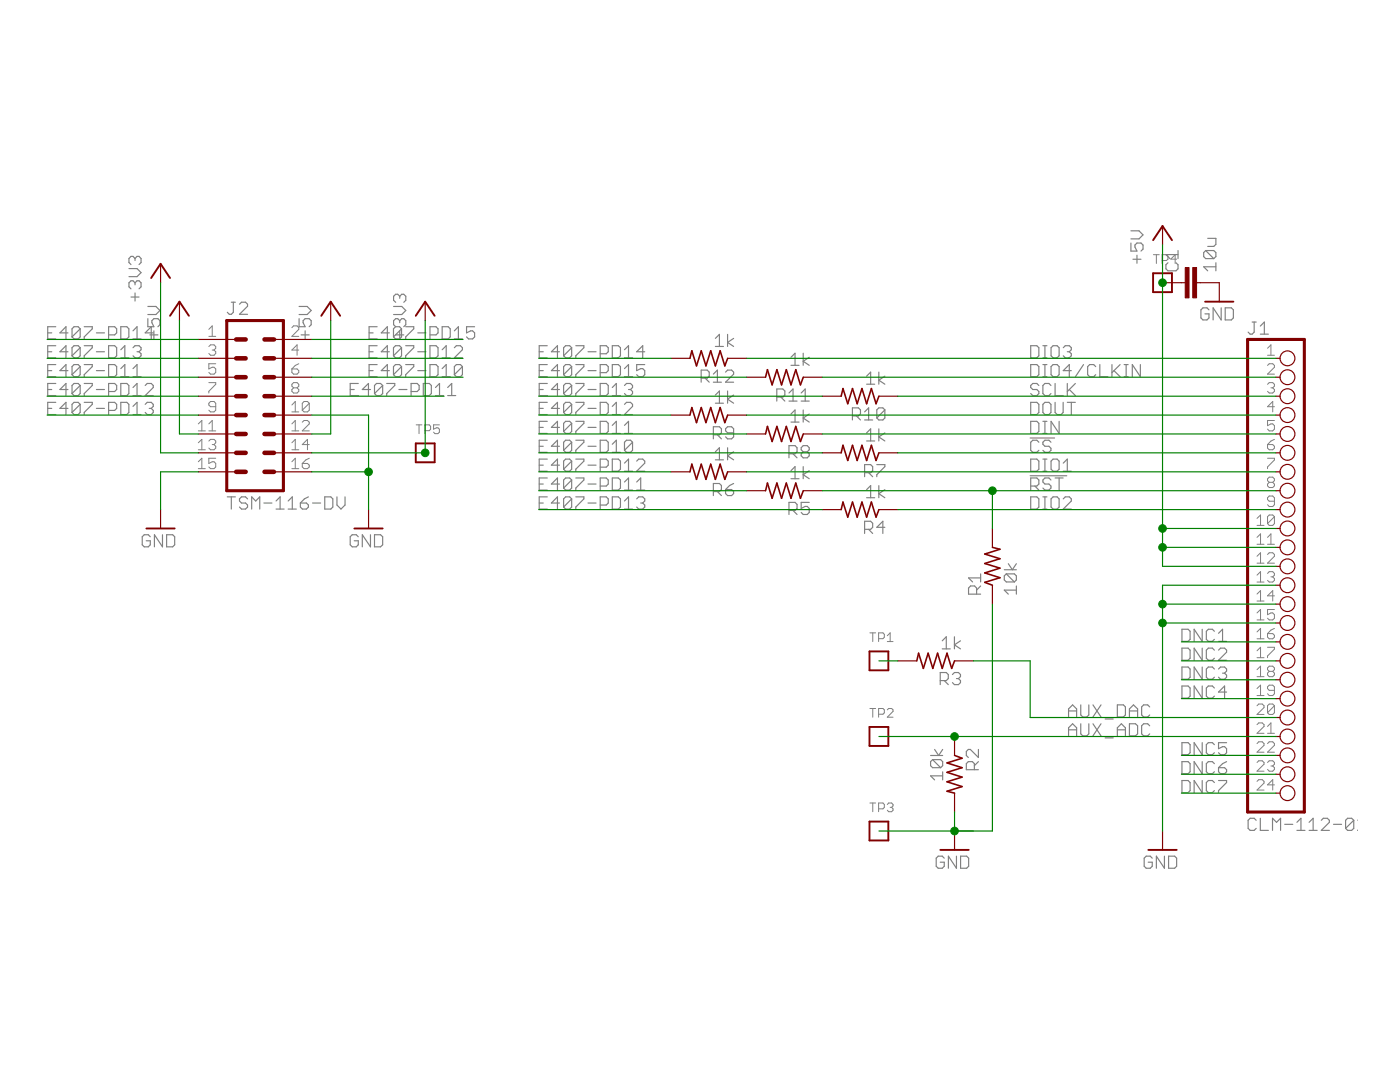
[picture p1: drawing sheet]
<svg xmlns="http://www.w3.org/2000/svg" width="279mm" height="216mm" viewBox="0 0 279 216" stroke-linecap="round" stroke-linejoin="round" font-family="sans-serif">
<g fill="none" stroke="#808080" stroke-width=".23">
<path d="M25.7 53.6h1.6l.9 .8-.9 .8h-1.6M26.1 59.3h1.6M26.9 51.6v.4M26.9 56.4v.4M26.9 58.5v1.6M26.9 56.4l-.4-.4h-.4l-.4 .4v.8l.4 .4M26.9 51.6l-.4-.4h-.4l-.4 .4v.8l.4 .4M26.9 56.4l.4-.4h.4l.5 .4v.8l-.5 .4M26.9 51.6l.4-.4h.4l.5 .4v.8l-.5 .4M79.8 59.1v.4M79.8 59.1l-.4-.4h-.4l-.5 .4v.8l.5 .4M79.8 59.1l.4-.4h.4l.4 .4v.8l-.4 .4"/>
<path d="M225.7 48.5v1.6h1.2l-.4-.8v-.4l.4-.4h.8l.4 .4v.8l-.4 .4M225.7 46.1h1.6l.8 .8-.8 .8h-1.6M226.1 51.7h1.6M226.9 50.9v1.6M233.1 52.4l-.4 .4v.8l.4 .4h1.6l.4-.4v-.8l-.4-.4M235.1 50v1.6M235.1 50.8h-2.4l.8 .8M240.6 50h1.6l.5 .4v.8l-.5 .4M240.6 50l-.4 .4v.8l.4 .4h1.6M240.6 50l1.6 1.6M241 47.6h1.7v1.2l-.5 .4h-1.2M242.7 53.2h-2.5l.8 .8"/>
<path d="M242.7 52.4v1.6M9.5 74h.8M9.5 70.2h.8M9.5 77.7h.8M9.5 66.4h.8M11.1 65.2h-1.6v2.4h1.6M11.1 72.7h-1.6v2.5h1.6M11.1 69h-1.6v2.4h1.6M11.1 76.5h-1.6v2.4h1.6M13.6 70.2h-1.6l1.2-1.2v2.4M13.6 74h-1.6l1.2-1.3v2.5M13.6 77.7h-1.6l1.2-1.2v2.4"/>
<path d="M13.6 66.4h-1.6l1.2-1.2v2.4M16 65.6l-.4-.4h-.8l-.4 .4v1.6M16 73.2v1.6l-.4 .4h-.8l-.4-.4M16 73.2l-.4-.5h-.8l-.4 .5v1.6M16 69.4v1.6l-.4 .4h-.8l-.4-.4M16 69.4l-.4-.4h-.8l-.4 .4v1.6M16 76.9l-.4-.4h-.8l-.4 .4v1.6M16 76.9v1.6l-.4 .4h-.8l-.4-.4M16 65.6v1.6l-.4 .4h-.8l-.4-.4M16 65.6l-1.6 1.6M16 69.4l-1.6 1.6M16 73.2l-1.6 1.6"/>
<path d="M16 76.9l-1.6 1.6M16.8 65.2h1.6v.4l-1.6 1.6v.4M16.8 72.7h1.6v.5l-1.6 1.6v.4M16.8 69h1.6v.4l-1.6 1.6v.4M16.8 76.5h1.6v.4l-1.6 1.6v.4M19.2 74h1.6M19.2 70.2h1.6M19.2 77.7h1.6M19.2 66.4h1.6M21.7 66.8h1.2l.4-.4v-.8l-.4-.4h-1.2v2.4M21.7 69h1.2l.4 .4v1.6l-.4 .4h-1.2zM21.7 72.7h1.2l.4 .5v1.6l-.4 .4h-1.2z"/>
<path d="M21.7 78.1h1.2l.4-.4v-.8l-.4-.4h-1.2v2.4M24.1 65.2h1.2l.4 .4v1.6l-.4 .4h-1.2zM24.1 75.2h1.6M24.1 71.4h1.6M24.1 76.5h1.2l.4 .4v1.6l-.4 .4h-1.2zM24.1 69.8l.8-.8v2.4M24.1 73.6l.8-.9v2.5M26.5 69.4l.4-.4h.8l.5 .4v.4l-.5 .4M26.5 75.2h1.7M26.5 78.9h1.7M26.5 67.6h1.7M26.5 66l.8-.8v2.4"/>
<path d="M26.5 73.6l.8-.9v2.5M26.5 77.3l.8-.8v2.4M27.3 70.2h.4M27.7 70.2l.5 .4v.4l-.5 .4h-.8l-.4-.4M29 76.9l.4-.4h.8l.4 .4v.4l-1.6 1.6h1.6M29.5 63.6v1.6h1.2l-.4-.8v-.4l.4-.4h.8l.4 .4v.8l-.4 .4M29.5 61.2h1.6l.8 .8-.8 .8h-1.6M29.9 66.8h1.6M30.6 66.4h-1.6l1.2-1.2v2.4M30.7 66v1.6M46.2 60.3h.8M46.6 60.3v2l-.4 .4h-.4l-.4-.4"/>
<path d="M47.8 60.7l.4-.4h.8l.4 .4v.4l-1.6 1.6h1.6M59.7 63.6v1.6h1.2l-.4-.8v-.4l.4-.4h.8l.4 .4v.8l-.4 .4M59.7 61.2h1.6l.8 .8-.8 .8h-1.6M60.1 66.8h1.6M60.9 66v1.6M69.9 77.7h.8M71.5 76.5h-1.6v2.4h1.6M73.7 74h.8M73.7 70.2h.8M73.7 66.4h.8M73.9 77.7h-1.6l1.2-1.2v2.4M75.3 65.2h-1.6v2.4h1.6"/>
<path d="M75.3 72.7h-1.6v2.5h1.6M75.3 69h-1.6v2.4h1.6M76.4 76.9l-.5-.4h-.8l-.4 .4v1.6M76.4 76.9v1.6l-.5 .4h-.8l-.4-.4M76.4 76.9l-1.7 1.6M77.2 76.5h1.6v.4l-1.6 1.6v.4M77.7 74h-1.6l1.2-1.3v2.5M77.7 70.2h-1.6l1.2-1.2v2.4M77.7 66.4h-1.6l1.2-1.2v2.4M78.5 61.2h1.7l.8 .8-.8 .8h-1.7M79 66.8h1.6M79.6 77.7h1.6"/>
<path d="M79.8 64l-.4-.4h-.4l-.5 .4v.8l.5 .4M79.8 64l.4-.4h.4l.4 .4v.8l-.4 .4M79.8 64v.4M79.8 66v1.6M80.1 65.6l-.4-.4h-.8l-.4 .4v1.6M80.1 69.4l-.4-.4h-.8l-.4 .4v1.6M80.1 73.2l-.4-.5h-.8l-.4 .5v1.6M80.1 65.6l-1.6 1.6M80.1 73.2v1.6l-.4 .4h-.8l-.4-.4M80.1 69.4v1.6l-.4 .4h-.8l-.4-.4M80.1 65.6v1.6l-.4 .4h-.8l-.4-.4M80.1 69.4l-1.6 1.6"/>
<path d="M80.1 73.2l-1.6 1.6M81 65.2h1.6v.4l-1.6 1.6v.4M81 69h1.6v.4l-1.6 1.6v.4M81 72.7h1.6v.5l-1.6 1.6v.4M82 78.1h1.2l.5-.4v-.8l-.5-.4h-1.2v2.4M83.4 74h1.6M83.4 70.2h1.6M83.4 66.4h1.6M84.5 76.5h1.2l.4 .4v1.6l-.4 .4h-1.2zM85.8 66.8h1.2l.4-.4v-.8l-.4-.4h-1.2v2.4M85.8 72.7h1.2l.4 .5v1.6l-.4 .4h-1.2zM85.8 69h1.2l.4 .4v1.6l-.4 .4h-1.2z"/>
<path d="M86.9 78.9h1.6M86.9 77.3l.8-.8v2.4M88.2 65.2h1.3l.4 .4v1.6l-.4 .4h-1.3zM88.2 75.2h1.7M88.2 71.4h1.7M88.2 69.8l.8-.8v2.4M88.2 73.6l.8-.9v2.5M89.3 78.9h1.7M89.3 77.3l.8-.8v2.4M90.7 69.4l.4-.4h.8l.4 .4v.4l-1.6 1.6h1.6M90.7 67.6h1.6M90.7 66l.8-.8v2.4"/>
<path d="M92.3 73.2v1.6l-.4 .4h-.8l-.4-.4M92.3 73.2l-.4-.5h-.8l-.4 .5v1.6M92.3 73.2l-1.6 1.6M94.7 65.2h-1.6v1.2l.8-.4h.4l.4 .4v.8l-.4 .4h-.8l-.4-.4M107.6 74h.8M107.6 70.2h.8M107.6 77.7h.8M109.2 72.7h-1.6v2.5h1.6M109.2 69h-1.6v2.4h1.6M109.2 76.5h-1.6v2.4h1.6M111.7 70.2h-1.7l1.3-1.2v2.4M111.7 74h-1.7l1.3-1.3v2.5"/>
<path d="M111.7 77.7h-1.7l1.3-1.2v2.4M114.1 73.2v1.6l-.4 .4h-.8l-.4-.4M114.1 73.2l-.4-.5h-.8l-.4 .5v1.6M114.1 69.4v1.6l-.4 .4h-.8l-.4-.4M114.1 69.4l-.4-.4h-.8l-.4 .4v1.6M114.1 76.9l-.4-.4h-.8l-.4 .4v1.6M114.1 76.9v1.6l-.4 .4h-.8l-.4-.4M114.1 69.4l-1.6 1.6M114.1 73.2l-1.6 1.6M114.1 76.9l-1.6 1.6M114.9 72.7h1.6v.5l-1.6 1.6v.4M114.9 69h1.6v.4l-1.6 1.6v.4"/>
<path d="M114.9 76.5h1.6v.4l-1.6 1.6v.4M117.3 74h1.7M117.3 70.2h1.7M117.3 77.7h1.7M119.8 74.4h1.2l.4-.4v-.8l-.4-.5h-1.2v2.5M119.8 70.6h1.2l.4-.4v-.8l-.4-.4h-1.2v2.4M119.8 76.5h1.2l.4 .4v1.6l-.4 .4h-1.2zM122.2 72.7h1.2l.4 .5v1.6l-.4 .4h-1.2zM122.2 69h1.2l.4 .4v1.6l-.4 .4h-1.2zM122.2 78.9h1.6M122.2 77.3l.8-.8v2.4M124.6 75.2h1.6"/>
<path d="M124.6 71.4h1.6M124.6 76.9l.4-.4h.8l.4 .4v.4l-.4 .4M124.6 69.8l.8-.8v2.4M124.6 73.6l.8-.9v2.5M125.4 77.7h.4M125.8 77.7l.4 .4v.4l-.4 .4h-.8l-.4-.4M128.7 72.7h-1.6v1.3l.8-.4h.4l.4 .4v.8l-.4 .4h-.8l-.4-.4M128.7 70.2h-1.6l1.2-1.2v2.4M139.9 75.5h1.2l.4-.4v-.8l-.4-.4h-1.2v2.4M140.7 75.5l.8 .8M142.4 74.7l.8-.8v2.4M142.4 76.3h1.6"/>
<path d="M142.8 67.5l.8-.8v2.4M142.8 78.8l.8-.8v2.5M142.8 69.1h1.6M144.8 74.3l.4-.4h.8l.4 .4v.4l-1.6 1.6h1.6M145.2 66.7v2.4M145.2 78v2.5M146.4 78.8l-1.2 .9 1.2 .8M146.4 67.5l-1.2 .8 1.2 .8M155 79.2h1.2l.4-.4v-.8l-.4-.4h-1.2v2.4M155.8 79.2l.8 .8M157.5 78.4l.8-.8v2.4M157.9 71.3l.8-.8v2.4"/>
<path d="M157.9 72.9h1.6M159.9 78.4l.8-.8v2.4M160.3 70.5v2.4M161.5 71.3l-1.2 .8 1.2 .8M173 75.1l.8-.8v2.4M173 76.7h1.6M175.4 74.3v2.4M176.6 75.1l-1.2 .8 1.2 .8M205.7 69h1.2l.4 .4v1.6l-.4 .4h-1.2zM205.7 72.7h1.2l.4 .5v1.6l-.4 .4h-1.2zM207.3 76.9l-.4-.4h-.8l-.4 .4v.4l.4 .4h.8l.4 .4v.4l-.4 .4h-.8l-.4-.4M208.1 75.2h.8"/>
<path d="M208.1 72.7h.8M208.1 71.4h.8M208.1 69h.8M208.5 69v2.4M208.5 72.7v2.5M209.7 76.9l-.4-.4h-.8l-.4 .4v1.6l.4 .4h.8l.4-.4M209.8 73.2l.4-.5h.8l.4 .5v1.6l-.4 .4h-.8l-.4-.4zM210.2 69h.8l.4 .4v1.6l-.4 .4h-.8l-.4-.4v-1.6zM210.6 76.5v2.4h1.6M212.2 69.4l.4-.4h.8l.4 .4v.4l-.4 .4M213 70.2h.4M213 76.5v2.4"/>
<path d="M213.4 70.2l.4 .4v.4l-.4 .4h-.8l-.4-.4M213.4 77.7l1.2 1.2M213.8 74h-1.6l1.2-1.3v2.5M214.6 76.5l-1.6 1.6M216.2 72.7l-1.6 2.5M218.7 73.2l-.4-.5h-.8l-.4 .5v1.6l.4 .4h.8l.4-.4M219.5 72.7v2.5h1.6M221.9 72.7v2.5M222.3 74l1.2 1.2M223.5 72.7l-1.6 1.7M224.3 75.2h.8M224.3 72.7h.8"/>
<path d="M224.7 72.7v2.5M227.6 72.7v2.5l-1.6-2.5v2.5M241.3 61.8l-.4-.4h-.8l-.4 .4v1.6l.4 .4h.8l.4-.4v-.8h-.8M243.7 61.4v2.4l-1.6-2.4v2.4M244.5 61.4h1.2l.4 .4v1.6l-.4 .4h-1.2zM249.9 64.3h.8M250.3 64.3v2l-.4 .4h-.4l-.4-.4M251.5 66.7h1.6M251.5 65.1l.8-.8v2.4M9.5 81.5h.8M11.1 80.3h-1.6v2.4h1.6M13.6 81.5h-1.6l1.2-1.2v2.4"/>
<path d="M16 80.7v1.6l-.4 .4h-.8l-.4-.4M16 80.7l-.4-.4h-.8l-.4 .4v1.6M16 80.7l-1.6 1.6M16.8 80.3h1.6v.4l-1.6 1.6v.4M19.2 81.5h1.6M21.7 81.9h1.2l.4-.4v-.8l-.4-.4h-1.2v2.4M24.1 80.3h1.2l.4 .4v1.6l-.4 .4h-1.2zM26.5 82.7h1.7M26.5 81.1l.8-.8v2.4M29 80.7l.4-.4h.8l.4 .4v.4l-.4 .4M29.8 81.5h.4M30.2 81.5l.4 .4v.4l-.4 .4h-.8l-.4-.4"/>
<path d="M45.4 99.1h1.6M46.2 99.1v2.5M49.4 99.5l-.4-.4h-.8l-.4 .4v.5l.4 .4h.8l.4 .4v.4l-.4 .4h-.8l-.4-.4M55.1 100l.8-.9v2.5M57.5 100l.8-.9v2.5M61.6 99.1l-.9 .4-.8 .9M64.8 99.1h1.2l.4 .4v1.7l-.4 .4h-1.2zM67.2 99.1v1.7l.9 .8 .8-.8v-1.7M107.6 89h.8M107.6 96.6h.8M107.6 81.5h.8M107.6 85.3h.8"/>
<path d="M107.6 92.8h.8M109.2 99.1h-1.6v2.5h1.6M109.2 80.3h-1.6v2.4h1.6M109.2 87.8h-1.6v2.5h1.6M109.2 91.6h-1.6v2.4h1.6M109.2 95.4h-1.6v2.4h1.6M109.2 84.1h-1.6v2.4h1.6M111.7 89h-1.7l1.3-1.2v2.5M111.7 96.6h-1.7l1.3-1.2v2.4M111.7 81.5h-1.7l1.3-1.2v2.4M111.7 85.3h-1.7l1.3-1.2v2.4M111.7 92.8h-1.7l1.3-1.2v2.4"/>
<path d="M114.1 99.5l-.4-.4h-.8l-.4 .4v1.7M114.1 99.5v1.7l-.4 .4h-.8l-.4-.4M114.1 80.7v1.6l-.4 .4h-.8l-.4-.4M114.1 80.7l-.4-.4h-.8l-.4 .4v1.6M114.1 88.2l-.4-.4h-.8l-.4 .4v1.7M114.1 88.2v1.7l-.4 .4h-.8l-.4-.4M114.1 92v1.6l-.4 .4h-.8l-.4-.4M114.1 92l-.4-.4h-.8l-.4 .4v1.6M114.1 95.8l-.4-.4h-.8l-.4 .4v1.6M114.1 95.8v1.6l-.4 .4h-.8l-.4-.4M114.1 84.5l-.4-.4h-.8l-.4 .4v1.6M114.1 84.5v1.6l-.4 .4h-.8l-.4-.4"/>
<path d="M114.1 80.7l-1.6 1.6M114.1 84.5l-1.6 1.6M114.1 88.2l-1.6 1.7M114.1 92l-1.6 1.6M114.1 95.8l-1.6 1.6M114.1 99.5l-1.6 1.7M114.9 99.1h1.6v.4l-1.6 1.7v.4M114.9 80.3h1.6v.4l-1.6 1.6v.4M114.9 87.8h1.6v.4l-1.6 1.7v.4M114.9 91.6h1.6v.4l-1.6 1.6v.4M114.9 95.4h1.6v.4l-1.6 1.6v.4M114.9 84.1h1.6v.4l-1.6 1.6v.4"/>
<path d="M117.3 89h1.7M117.3 96.6h1.7M117.3 81.5h1.7M117.3 85.3h1.7M117.3 92.8h1.7M119.8 80.3h1.2l.4 .4v1.6l-.4 .4h-1.2zM119.8 87.8h1.2l.4 .4v1.7l-.4 .4h-1.2zM119.8 93.2h1.2l.4-.4v-.8l-.4-.4h-1.2v2.4M119.8 97h1.2l.4-.4v-.8l-.4-.4h-1.2v2.4M119.8 84.1h1.2l.4 .4v1.6l-.4 .4h-1.2zM122.2 99.1h1.2l.4 .4v1.7l-.4 .4h-1.2zM122.2 82.7h1.6"/>
<path d="M122.2 90.3h1.6M122.2 91.6h1.2l.4 .4v1.6l-.4 .4h-1.2zM122.2 95.4h1.2l.4 .4v1.6l-.4 .4h-1.2zM122.2 81.1l.8-.8v2.4M122.2 84.9l.8-.8v2.4M122.2 88.6l.8-.8v2.5M122.2 86.5h1.6M124.6 92.4l.8-.8v2.4M124.6 80.7l.4-.4h.8l.4 .4v.4l-1.6 1.6h1.6M124.6 94h1.6M124.6 97.8h1.6M124.6 86.5h1.6"/>
<path d="M124.6 84.9l.8-.8v2.4M124.6 96.2l.8-.8v2.4M124.6 100l.8-.9v2.5M126.2 88.2l-.4-.4h-.8l-.4 .4v1.7M126.2 88.2v1.7l-.4 .4h-.8l-.4-.4M126.2 88.2l-1.6 1.7M127.1 99.5l.4-.4h.8l.4 .4v.5l-.4 .4M127.1 92l.4-.4h.8l.4 .4v.4l-1.6 1.6h1.6M127.1 97.8h1.6M127.1 96.2l.8-.8v2.4M142.4 86.8h1.2l.4-.4v-.8l-.4-.4h-1.2v2.4M142.4 98.1h1.2l.4-.4v-.8l-.4-.4h-1.2v2.4"/>
<path d="M142.8 90.1l.8-.8v2.5M142.8 91.8h1.6M142.8 80.5h1.6M143.2 98.1l.8 .8M143.2 86.8l.8 .8M144.8 97.7h1.2l.4 .4v.4l-.4 .4h-.8l-.4-.4zM145.2 89.3v2.5M146.4 90.1l-1.2 .9 1.2 .8M146.4 86.4h-1.2l-.4-.4v-.4l.4-.4h.8l.4 .4v1.6l-.4 .4h-.8l-.4-.4M146.4 96.5l-.8 .4-.8 .8M157.5 90.6h1.2l.4-.5v-.8l-.4-.4h-1.2v2.5M157.5 80h1.6"/>
<path d="M157.9 93.9l.8-.8v2.4M157.9 82.6l.8-.8v2.4M157.9 95.5h1.6M157.9 84.2h1.6M158.3 90.6l.8 .8M159.9 80h1.6M160.3 81.8v2.4M160.3 93.1v2.4M160.3 90.1l-.4-.4v-.4l.4-.4h.8l.4 .4v.4l-.4 .4M160.3 90.1l-.4 .5v.4l.4 .4h.8l.4-.4v-.4l-.4-.5M160.3 90.1h.8M161.5 93.9l-1.2 .8 1.2 .8"/>
<path d="M161.5 82.6l-1.2 .8 1.2 .8M170.1 83h1.2l.4-.4v-.8l-.4-.4h-1.2v2.4M170.9 83l.8 .8M172.6 94.3h1.2l.4-.4v-.8l-.4-.4h-1.2v2.4M172.6 82.2l.8-.8v2.4M172.6 83.8h1.6M173 97.7l.8-.8v2.4M173 86.4l.8-.8v2.4M173 99.3h1.6M173 88h1.6M173.4 94.3l.8 .8M175 92.7h1.6v.4l-1.6 1.6v.4"/>
<path d="M175.4 85.6v2.4M175.4 96.9v2.4M176.6 97.7l-1.2 .8 1.2 .8M176.6 86.4l-1.2 .8 1.2 .8M176.6 81.8v1.6l-.4 .4h-.8l-.4-.4M176.6 81.8l-.4-.4h-.8l-.4 .4v1.6M176.6 81.8l-1.6 1.6M205.6 87.4h4.9M205.6 94.9h7.3M205.7 99.1h1.2l.4 .4v1.7l-.4 .4h-1.2zM205.7 80.3h1.2l.4 .4v1.6l-.4 .4h-1.2zM205.7 84.1h1.2l.4 .4v1.6l-.4 .4h-1.2z"/>
<path d="M205.7 91.6h1.2l.4 .4v1.6l-.4 .4h-1.2zM205.7 97h1.2l.4-.4v-.8l-.4-.4h-1.2v2.4M206.5 97l.8 .8M207.3 88.2l-.4-.4h-.8l-.4 .4v1.7l.4 .4h.8l.4-.4M208.1 99.1h.8M208.1 80.7l.4-.4h.8l.4 .4v1.6l-.4 .4h-.8l-.4-.4zM208.1 94h.8M208.1 91.6h.8M208.1 86.5h.8M208.1 84.1h.8M208.5 84.1v2.4M208.5 91.6v2.4"/>
<path d="M208.5 99.1v2.5M209.7 88.2l-.4-.4h-.8l-.4 .4v.4l.4 .4h.8l.4 .5v.4l-.4 .4h-.8l-.4-.4M209.7 95.8l-.4-.4h-.8l-.4 .4v.4l.4 .4h.8l.4 .4v.4l-.4 .4h-.8l-.4-.4M209.8 92l.4-.4h.8l.4 .4v1.6l-.4 .4h-.8l-.4-.4zM210.2 99.1h.8l.4 .4v1.7l-.4 .4h-.8l-.4-.4v-1.7zM210.6 80.3v2l.4 .4h.8l.4-.4v-2M210.6 95.4h1.6M211.4 84.1v2.4l-1.6-2.4v2.4M211.4 95.4v2.4M212.2 99.5l.4-.4h.8l.4 .4v.5l-1.6 1.6h1.6M212.2 92.4l.8-.8v2.4M212.2 94h1.6"/>
<path d="M213 80.3h1.6M213.8 80.3v2.4M30 107.1l-.4-.4h-.8l-.4 .4v1.6l.4 .4h.8l.4-.4v-.8h-.8M32.4 106.7v2.4l-1.6-2.4v2.4M33.3 106.7h1.2l.4 .4v1.6l-.4 .4h-1.2zM50.2 101.6v-2.5l.8 .9 .8-.9v2.5M52.7 100.4h1.6M55.1 101.6h1.6M57.5 101.6h1.6M59.9 100.4h1.3l.4 .4v.4l-.4 .4h-.9l-.4-.4zM62.4 100.4h1.6M71.5 107.1l-.4-.4h-.8l-.4 .4v1.6l.4 .4h.8l.4-.4v-.8h-.8"/>
<path d="M73.9 106.7v2.4l-1.6-2.4v2.4M74.7 106.7h1.2l.5 .4v1.6l-.5 .4h-1.2zM107.6 100.4h.8M111.7 100.4h-1.7l1.3-1.3v2.5M117.3 100.4h1.7M119.8 100.8h1.2l.4-.4v-.9l-.4-.4h-1.2v2.5M124.6 101.6h1.6M127.9 100.4h.4M128.3 100.4l.4 .4v.4l-.4 .4h-.8l-.4-.4M157.5 101.9h1.2l.4-.4v-.9l-.4-.4h-1.2v2.5M158.3 101.9l.8 .8M161.5 100.2h-1.6v1.3l.8-.5h.4l.4 .5v.8l-.4 .4h-.8l-.4-.4"/>
<path d="M172.6 105.6h1.2l.4-.4v-.8l-.4-.4h-1.2v2.4M173.4 105.6l.8 .8M176.6 105.2h-1.6l1.2-1.2v2.4M194.9 118.6v-1.3l-.4-.4h-.8l-.4 .4v1.3h2.4M195.7 116.9l-.8 .9M195.7 115.3h-2.4l.8 .8M195.7 114.5v1.6M200.4 113.7h2.4M200.8 114.5h1.6l.4 .4v.8l-.4 .4M200.8 114.5l-.4 .4v.8l.4 .4h1.6M200.8 114.5l1.6 1.6M201.2 112.5l.8 1.2 .8-1.2"/>
<path d="M202.8 117.8h-2.4l.8 .8M202.8 116.9v1.7M208.1 101.6h.8M187.6 135.8h1.2l.5-.4v-.8l-.5-.4h-1.2v2.4M188 127.9l.8-.8v2.4M188 129.5h1.7M188.4 135.8l.9 .8M190.1 134.6l.4-.4h.8l.4 .4v.4l-.4 .4M190.5 127.1v2.4M190.9 135.4h.4M191.3 135.4l.4 .4v.4l-.4 .4h-.8l-.4-.4M191.7 127.9l-1.2 .8 1.2 .8"/>
<path d="M235.9 125.6h1.2l.4 .4v1.6l-.4 .4h-1.2zM235.9 129.3h1.2l.4 .4v1.6l-.4 .4h-1.2zM235.9 133.1h1.2l.4 .4v1.6l-.4 .4h-1.2zM235.9 136.9h1.2l.4 .4v1.6l-.4 .4h-1.2zM239.9 125.6v2.4l-1.6-2.4v2.4M239.9 129.3v2.4l-1.6-2.4v2.4M239.9 133.1v2.4l-1.6-2.4v2.4M239.9 136.9v2.4l-1.6-2.4v2.4M242.4 126l-.4-.4h-.8l-.5 .4v1.6l.5 .4h.8l.4-.4M242.4 129.7l-.4-.4h-.8l-.5 .4v1.6l.5 .4h.8l.4-.4M242.4 133.5l-.4-.4h-.8l-.5 .4v1.6l.5 .4h.8l.4-.4M242.4 137.3l-.4-.4h-.8l-.5 .4v1.6l.5 .4h.8l.4-.4"/>
<path d="M243.2 128h1.6M243.2 126.4l.8-.8v2.4M243.2 129.7l.4-.4h.8l.4 .4v.4l-1.6 1.6h1.6M243.2 133.5l.4-.4h.8l.4 .4v.4l-.4 .4M244 134.3h.4M244.4 134.3l.4 .4v.4l-.4 .4h-.8l-.4-.4M244.8 138.1h-1.6l1.2-1.2v2.4M185.7 150.7h2.4M186.1 151.6h1.6l.4 .4v.8l-.4 .4M186.1 151.6l-.4 .4v.8l.4 .4h1.6M186.1 151.6l1.6 1.6M186.5 149.5l.8 1.2 .8-1.2"/>
<path d="M188.1 154.8h-2.4l.8 .8M188.1 154v1.6M194.5 153.6v-1.2l-.4-.4h-.8l-.5 .4v1.2h2.5M195.3 149.5v1.7l-1.6-1.7h-.4l-.5 .4v.8l.5 .5M195.3 152l-.8 .8M213.3 143.1v-1.6l.8-.8 .8 .8v1.6M213.3 146.8v-1.6l.8-.8 .8 .8v1.6M213.3 141.9h1.6M213.3 145.6h1.6M215.7 140.7v2l.4 .4h.8l.4-.4v-2M215.7 144.4v2l.4 .4h.8l.4-.4v-2M218.1 140.7l1.6 2.4"/>
<path d="M218.1 144.4l1.6 2.4M219.7 140.7l-1.6 2.4M219.7 144.4l-1.6 2.4M220.6 143.5h1.6M220.6 147.2h1.6M223 140.7h1.2l.4 .4v1.6l-.4 .4h-1.2zM223 146.8v-1.6l.8-.8 .8 .8v1.6M223 145.6h1.6M225.4 141.9h1.6M225.4 143.1v-1.6l.8-.8 .8 .8v1.6M225.4 144.4h1.2l.4 .4v1.6l-.4 .4h-1.2zM229.4 141.1l-.4-.4h-.8l-.4 .4v1.6l.4 .4h.8l.4-.4"/>
<path d="M229.4 144.8l-.4-.4h-.8l-.4 .4v1.6l.4 .4h.8l.4-.4M235.9 152h1.2l.4 .4v1.6l-.4 .4h-1.2zM235.9 148.2h1.2l.4 .4v1.6l-.4 .4h-1.2zM235.9 155.7h1.2l.4 .4v1.7l-.4 .4h-1.2zM239.9 148.2v2.4l-1.6-2.4v2.4M239.9 152v2.4l-1.6-2.4v2.4M239.9 155.7v2.5l-1.6-2.5v2.5M242.4 152.4l-.4-.4h-.8l-.5 .4v1.6l.5 .4h.8l.4-.4M242.4 148.6l-.4-.4h-.8l-.5 .4v1.6l.5 .4h.8l.4-.4M242.4 156.1l-.4-.4h-.8l-.5 .4v1.7l.5 .4h.8l.4-.4M243.2 153.2h1.2l.4 .4v.4l-.4 .4h-.8l-.4-.4zM243.2 155.7h1.6v.4l-1.6 1.7v.4"/>
<path d="M244.8 148.2h-1.6v1.2l.8-.4h.4l.4 .4v.8l-.4 .4h-.8l-.4-.4M244.8 152l-.8 .4-.8 .8M188.4 171.2l-.4-.4h-.8l-.4 .4v1.6l.4 .4h.8l.4-.4v-.8h-.8M190.9 170.8v2.4l-1.6-2.4v2.4M191.7 170.8h1.2l.4 .4v1.6l-.4 .4h-1.2zM230 171.2l-.4-.4h-.9l-.4 .4v1.6l.4 .4h.9l.4-.4v-.8h-.8M232.4 170.8v2.4l-1.6-2.4v2.4M233.2 170.8h1.2l.4 .4v1.6l-.4 .4h-1.2zM250.7 163.7l-.4-.4h-.8l-.4 .4v1.6l.4 .4h.8l.4-.4M251.5 163.3v2.4h1.6M254 165.7v-2.4l.8 .8 .8-.8v2.4M256.4 164.5h1.6"/>
<path d="M258.8 165.7h1.6M258.8 164.1l.8-.8v2.4M261.3 165.7h1.6M261.3 164.1l.8-.8v2.4M263.7 163.7l.4-.4h.8l.4 .4v.4l-1.6 1.6h1.6M266.1 164.5h1.6M270.2 163.7l-.5-.4h-.8l-.4 .4v1.6M270.2 163.7v1.6l-.5 .4h-.8l-.4-.4M270.2 163.7l-1.7 1.6"/>
</g>
<g fill="none" stroke="#808080" stroke-width=".2">
<path d="M230.2 50.8h1.2M230.8 50.8v1.8M231.9 52h.9l.3-.3v-.6l-.3-.3h-.9v1.8M234.8 51.7h-1.1l.8-.9v1.8M41.7 76.3h1.4v.4l-1.4 1.4v.3M41.7 65.7l.7-.7v2.1M41.7 67.1h1.4M41.7 69.2l.3-.4h.7l.4 .4v.3l-.4 .3M42.4 69.8h.3M42.7 69.8l.4 .4v.3l-.4 .4h-.7l-.3-.4M43.1 72.6h-1.4v1l.7-.3h.3l.4 .3v.7l-.4 .4h-.7l-.3-.4M58.3 73.6h1l.3 .4v.3l-.3 .4h-.7l-.3-.4z"/>
<path d="M58.3 65.4l.3-.4h.7l.3 .4v.3l-1.3 1.4h1.3M58.6 77.4l-.3-.4v-.3l.3-.4h.7l.3 .4v.3l-.3 .4M58.6 77.4h.7M58.6 77.4l-.3 .3v.4l.3 .3h.7l.3-.3v-.4l-.3-.3M59.6 69.8h-1.3l1-1v2.1M59.6 72.6l-.7 .3-.6 .7M253 69.5l.6-.7v2.1M253 70.9h1.3M253 72.9l.3-.3h.7l.3 .3v.4l-1.3 1.4h1.3M253 76.7l.3-.4h.7l.3 .4v.3l-.3 .4M253.6 77.4h.4M254 77.4l.3 .3v.4l-.3 .3h-.7l-.3-.3"/>
<path d="M39.6 86h1.4M39.6 89.7h1.4M39.6 84.6l.7-.7v2.1M39.6 88.3l.7-.6v2M39.6 92.1l.7-.7v2.1M39.6 93.5h1.4M41.7 86h1.4M41.7 84.6l.7-.7v2.1M41.7 88l.3-.3h.7l.4 .3v.3l-.4 .4M42.4 88.7h.3M42.7 88.7l.4 .3v.4l-.4 .3h-.7l-.3-.3M43.1 81.2h-1.1l-.3-.4v-.3l.3-.4h.7l.4 .4v1.4l-.4 .3h-.7l-.3-.3"/>
<path d="M43.1 91.4h-1.4v1.1l.7-.4h.3l.4 .4v.7l-.4 .3h-.7l-.3-.3M58.3 86h1.3M58.3 89.7h1.3M58.3 82.2h1.3M58.3 80.8l.6-.7v2.1M58.3 84.6l.6-.7v2.1M58.3 88.3l.6-.6v2M58.3 92.1l.6-.7v2.1M58.3 93.5h1.3M60.3 84.2l.4-.3h.7l.3 .3v.4l-1.4 1.4h1.4M60.3 92.5h1.1l.3 .3v.4l-.3 .3h-.7l-.4-.3zM61.7 88.7h-1.4l1.1-1v2"/>
<path d="M61.7 80.5l-.3-.4h-.7l-.4 .4v1.4M61.7 80.5v1.4l-.3 .3h-.7l-.4-.3M61.7 80.5l-1.4 1.4M61.7 91.4l-.7 .4-.7 .7M83.1 84.8h1.1M83.6 84.8v1.7M84.8 85.9h.9l.2-.3v-.5l-.2-.3h-.9v1.7M87.7 84.8h-1.2v.8l.6-.2h.3l.3 .2v.6l-.3 .3h-.6l-.3-.3M253 88.7h1l.3 .3v.4l-.3 .3h-.7l-.3-.3zM253 91.4h1.3v.4l-1.3 1.4v.3M253.3 96.2l-.3-.3v-.3l.3-.4h.7l.3 .4v.3l-.3 .3M253.3 96.2l-.3 .4v.3l.3 .4h.7l.3-.4v-.3l-.3-.4"/>
<path d="M253.3 96.2h.7M254.3 83.9h-1.3v1l.6-.3h.4l.3 .3v.7l-.3 .4h-.7l-.3-.4M254.3 81.2h-1.3l1-1.1v2.1M254.3 87.7l-.7 .3-.6 .7M250.9 103.4l.7-.6v2M250.9 107.2l.7-.7v2.1M250.9 111l.7-.7v2.1M250.9 114.8l.7-.7v2M250.9 118.5l.7-.6v2M250.9 104.8h1.4M250.9 108.6h1.4M250.9 112.4h1.4"/>
<path d="M250.9 116.1h1.4M250.9 119.9h1.4M253 107.2l.6-.7v2.1M253 110.6l.3-.3h.7l.3 .3v.4l-1.3 1.4h1.3M253 114.4l.3-.3h.7l.3 .3v.4l-.3 .3M253 108.6h1.3M253.6 115.1h.4M254 115.1l.3 .4v.3l-.3 .3h-.7l-.3-.3M254.3 100h-1l-.3-.3v-.4l.3-.3h.7l.3 .3v1.4l-.3 .4h-.7l-.3-.4M254.3 103.1v1.4l-.3 .3h-.7l-.3-.3M254.3 118.9h-1.3l1-1v2M254.3 103.1l-.3-.3h-.7l-.3 .3v1.4"/>
<path d="M254.3 103.1l-1.3 1.4M173.6 126.3h1.2M174.2 126.3v1.7M175.3 127.4h.9l.3-.3v-.5l-.3-.3h-.9v1.7M177.1 126.9l.6-.6v1.7M177.1 128h1.1M250.9 122.3l.7-.7v2.1M250.9 126.1l.7-.7v2.1M250.9 129.9l.7-.7v2M250.9 133.6l.7-.7v2.1M250.9 137.4l.7-.7v2.1M250.9 123.7h1.4"/>
<path d="M250.9 127.5h1.4M250.9 131.2h1.4M250.9 135h1.4M250.9 138.8h1.4M253 126.4h1l.3 .4v.3l-.3 .4h-.7l-.3-.4zM253 129.2h1.3v.3l-1.3 1.4v.3M253.3 134l-.3-.4v-.3l.3-.4h.7l.3 .4v.3l-.3 .4M253.3 134l-.3 .3v.4l.3 .3h.7l.3-.3v-.4l-.3-.3M253.3 134h.7M254.3 121.6h-1.3v1.1l.6-.4h.4l.3 .4v.7l-.3 .3h-.7l-.3-.3M254.3 137.8h-1l-.3-.4v-.3l.3-.4h.7l.3 .4v1.3l-.3 .4h-.7l-.3-.4M254.3 125.4l-.7 .3-.6 .7"/>
<path d="M173.6 141.4h1.2M174.2 141.4v1.7M175.3 142.5h.9l.3-.3v-.6l-.3-.2h-.9v1.7M177.1 141.6l.3-.2h.5l.3 .2v.3l-1.1 1.2h1.1M250.9 140.8l.3-.3h.7l.4 .3v.4l-1.4 1.4h1.4M250.9 144.6l.3-.3h.7l.4 .3v.3l-1.4 1.4h1.4M250.9 148.4l.3-.4h.7l.4 .4v.3l-1.4 1.4h1.4M250.9 152.1l.3-.3h.7l.4 .3v.4l-1.4 1.4h1.4M250.9 155.9l.3-.3h.7l.4 .3v.4l-1.4 1.3h1.4M253 144.9l.6-.6v2M253 148.4l.3-.4h.7l.3 .4v.3l-1.3 1.4h1.3M253 152.1l.3-.3h.7l.3 .3v.4l-.3 .3"/>
<path d="M253 146.3h1.3M253.6 152.8h.4M254 152.8l.3 .4v.3l-.3 .4h-.7l-.3-.4M254.3 140.8v1.4l-.3 .4h-.7l-.3-.4M254.3 156.6h-1.3l1-1v2M254.3 140.8l-.3-.3h-.7l-.3 .3v1.4M254.3 140.8l-1.3 1.4M173.6 160.2h1.2M174.2 160.2v1.8M175.3 161.4h.9l.3-.3v-.6l-.3-.3h-.9v1.8M177.1 160.5l.3-.3h.5l.3 .3v.3l-.3 .3M177.7 161.1h.2"/>
<path d="M177.9 161.1l.3 .3v.3l-.3 .3h-.5l-.3-.3"/>
</g>
<g fill="none" stroke="#800000" stroke-width=".38">
<path d="M30.2 55.5l1.8-2.9 1.9 2.9M230.1 47.9l1.9-2.8 1.9 2.8M230.1 54.5h3.8v3.8h-3.8zM33.9 63l1.9-2.8 1.9 2.8M64.1 63l1.9-2.8 1.9 2.8M83 63l1.9-2.8 1.8 2.8M240.5 60.2h5.6M83 88.5h3.7v3.7h-3.7zM29.2 105.5h5.7M70.7 105.5h5.7M173.5 130h3.8v3.8h-3.8zM173.5 145.1h3.8v3.7h-3.8z"/>
<path d="M173.5 163.9h3.8v3.8h-3.8zM187.7 169.6h5.6M229.2 169.6h5.6"/>
</g>
<g fill="none" stroke="#800000" stroke-width=".23">
<path d="M32 52.6v3.8M232 45.1v3.8M232 56.4h4.5M238.8 56.4h4.5v3.8M35.8 60.2v3.8M39.6 79.1h7.5M39.6 75.3h7.5M39.6 71.5h7.5M39.6 67.7h7.5M54.7 79.1h7.5M54.7 75.3h7.5M54.7 71.5h7.5"/>
<path d="M54.7 67.7h7.5M66 60.2v3.8M84.9 60.2v3.8M133.9 71.5h3.8M145.2 71.5h3.8M149 75.3h3.8M160.3 75.3h3.8M164.1 79.1h3.8M175.4 79.1h3.8M254.6 79.1h.9M254.6 75.3h.9M254.6 71.5h.9"/>
<path d="M39.6 94.1h7.5M39.6 90.4h7.5M39.6 86.6h7.5M39.6 82.8h7.5M54.7 94.1h7.5M54.7 90.4h7.5M54.7 86.6h7.5M54.7 82.8h7.5M133.9 94.1h3.8M133.9 82.8h3.8M145.2 94.1h3.8M145.2 82.8h3.8"/>
<path d="M149 97.9h3.8M149 86.6h3.8M160.3 97.9h3.8M160.3 86.6h3.8M164.1 90.4h3.8M175.4 90.4h3.8M254.6 97.9h.9M254.6 94.1h.9M254.6 90.4h.9M254.6 86.6h.9M254.6 82.8h.9M32 101.7v3.8"/>
<path d="M73.6 101.7v3.8M164.1 101.7h3.8M175.4 101.7h3.8M198.1 105.5v3.7M198.1 116.8v3.7M254.6 101.7h.9M254.6 105.5h.9M254.6 109.2h.9M254.6 113h.9M254.6 116.8h.9M179.2 131.9h3.8M190.5 131.9h3.8"/>
<path d="M254.6 131.9h.9M254.6 120.5h.9M254.6 124.3h.9M254.6 128.1h.9M254.6 135.6h.9M254.6 139.4h.9M190.5 147v3.7M190.5 158.3v3.7M254.6 143.2h.9M254.6 147h.9M254.6 150.7h.9M254.6 154.5h.9"/>
<path d="M254.6 158.3h.9M190.5 165.8v3.8M232 165.8v3.8"/>
<circle cx="256.9" cy="75.3" r="1.48"/>
<circle cx="256.9" cy="79.1" r="1.48"/>
<circle cx="256.9" cy="71.5" r="1.48"/>
<circle cx="256.9" cy="90.4" r="1.48"/>
<circle cx="256.9" cy="97.9" r="1.48"/>
<circle cx="256.9" cy="94.1" r="1.48"/>
<circle cx="256.9" cy="86.6" r="1.48"/>
<circle cx="256.9" cy="82.8" r="1.48"/>
<circle cx="256.9" cy="105.5" r="1.48"/>
<circle cx="256.9" cy="101.7" r="1.48"/>
<circle cx="256.9" cy="109.2" r="1.48"/>
<circle cx="256.9" cy="116.8" r="1.48"/>
<circle cx="256.9" cy="113" r="1.48"/>
<circle cx="256.9" cy="139.4" r="1.48"/>
<circle cx="256.9" cy="120.5" r="1.48"/>
<circle cx="256.9" cy="124.3" r="1.48"/>
<circle cx="256.9" cy="128.1" r="1.48"/>
<circle cx="256.9" cy="131.9" r="1.48"/>
<circle cx="256.9" cy="135.6" r="1.48"/>
<circle cx="256.9" cy="143.2" r="1.48"/>
<circle cx="256.9" cy="154.5" r="1.48"/>
<circle cx="256.9" cy="158.3" r="1.48"/>
<circle cx="256.9" cy="150.7" r="1.48"/>
<circle cx="256.9" cy="147" r="1.48"/>
</g>
<path d="M137.7 71.5l.4-1.5 .9 3 1-3 .9 3 .9-3 1 3 .9-3 1 3 .5-1.5M152.8 75.3l.4-1.5 .9 3 .9-3 1 3 .9-3 1 3 .9-3 .9 3 .6-1.5M167.9 79.1l.3-1.6 1 3.1 .9-3.1 1 3.1 .9-3.1 1 3.1 .9-3.1 .9 3.1 .6-1.5M137.7 94.1l.4-1.5 .9 3.1 1-3.1 .9 3.1 .9-3.1 1 3.1 .9-3.1 1 3.1 .5-1.6M137.7 82.8l.4-1.5 .9 3 1-3 .9 3 .9-3 1 3 .9-3 1 3 .5-1.5M152.8 97.9l.4-1.5 .9 3 .9-3 1 3 .9-3 1 3 .9-3 .9 3 .6-1.5M152.8 86.6l.4-1.5 .9 3 .9-3 1 3 .9-3 1 3 .9-3 .9 3 .6-1.5M167.9 90.4l.3-1.5 1 3 .9-3 1 3 .9-3 1 3 .9-3 .9 3 .6-1.5M167.9 101.7l.3-1.5 1 3 .9-3 1 3 .9-3 1 3 .9-3 .9 3 .6-1.5M198.1 109.2l1.5 .4-3.1 1 3.1 .9-3.1 .9 3.1 1-3.1 .9 3.1 1-3.1 .9 1.6 .6M183 131.9l.3-1.6 1 3.1 .9-3.1 1 3.1 .9-3.1 .9 3.1 1-3.1 .9 3.1 .6-1.5M190.5 150.7l1.5 .6-3 .9 3 1-3 .9 3 1-3 .9 3 1-3 .9 1.5 .4" fill="none" stroke="#800000" stroke-width=".32"/>
<path d="M45.3 64h11.3v33.9h-11.3zM249 67.7h11.3v94.3h-11.3z" fill="none" stroke="#800000" stroke-width=".61"/>
<g fill="#800000" stroke="#800000" stroke-width=".2">
<path d="M238 53.4h.8v6h-.8z"/>
<path d="M236.5 53.4h.8v6h-.8z"/>
</g>
<g fill="none" stroke="#800000" stroke-width=".91">
<path d="M47.1 75.3h1.9M47.1 71.5h1.9M47.1 67.7h1.9M47.1 79.1h1.9M52.8 75.3h1.9M52.8 71.5h1.9M52.8 67.7h1.9M52.8 79.1h1.9M47.1 82.8h1.9M47.1 86.6h1.9M47.1 90.4h1.9M47.1 94.1h1.9"/>
<path d="M52.8 82.8h1.9M52.8 86.6h1.9M52.8 90.4h1.9M52.8 94.1h1.9"/>
</g>
<g fill="none" stroke="#008000" stroke-width=".23">
<path d="M32 56.4v34h7.6M232 48.9v64.1h22.6M9.4 75.3h30.2M9.4 71.5h30.2M9.4 79.1h30.2M9.4 67.7h30.2M35.8 64v22.6h3.8M62.2 75.3h30.2M62.2 71.5h30.2M62.2 79.1h26.4M62.2 67.7h30.2M66 64v22.6h-3.8"/>
<path d="M84.9 64v26.4h-22.7M107.5 75.3h41.5M107.5 71.5h26.4M107.5 79.1h56.6M149 71.5h105.6M164.1 75.3h90.5M179.2 79.1h75.4M9.4 82.8h30.2M39.6 94.1h-7.6v7.6M62.2 82.8h11.4v18.9M62.2 94.1h11.4M107.5 86.6h41.5"/>
<path d="M107.5 90.4h56.6M107.5 82.8h26.4M107.5 94.1h26.4M107.5 97.9h41.5M149 82.8h105.6M149 94.1h105.6M164.1 86.6h90.5M164.1 97.9h90.5M179.2 90.4h75.4M198.1 97.9v7.6M107.5 101.7h56.6M179.2 101.7h75.4"/>
<path d="M232 109.2h22.6M232 105.5h22.6M254.6 116.8h-22.6v49M175.4 131.9h3.8M194.3 131.9h11.3v11.3h49M198.1 120.5v45.3h-22.7M232 120.5h22.6M232 124.3h22.6M235.8 128.1h18.8M235.8 131.9h18.8M235.8 135.6h18.8M235.8 139.4h18.8"/>
<path d="M175.4 147h79.2M235.8 150.7h18.8M235.8 154.5h18.8M235.8 158.3h18.8M190.5 162v3.8"/>
</g>
<g fill="#008000" stroke="#008000" stroke-width=".2">
<circle cx="232" cy="109.2" r=".76"/>
<circle cx="232" cy="105.5" r=".76"/>
<circle cx="232" cy="56.4" r=".76"/>
<circle cx="84.9" cy="90.4" r=".76"/>
<circle cx="190.5" cy="147" r=".76"/>
<circle cx="198.1" cy="97.9" r=".76"/>
<circle cx="190.5" cy="165.8" r=".76"/>
<circle cx="73.6" cy="94.1" r=".76"/>
<circle cx="232" cy="120.5" r=".76"/>
<circle cx="232" cy="124.3" r=".76"/>
</g>
</svg>
